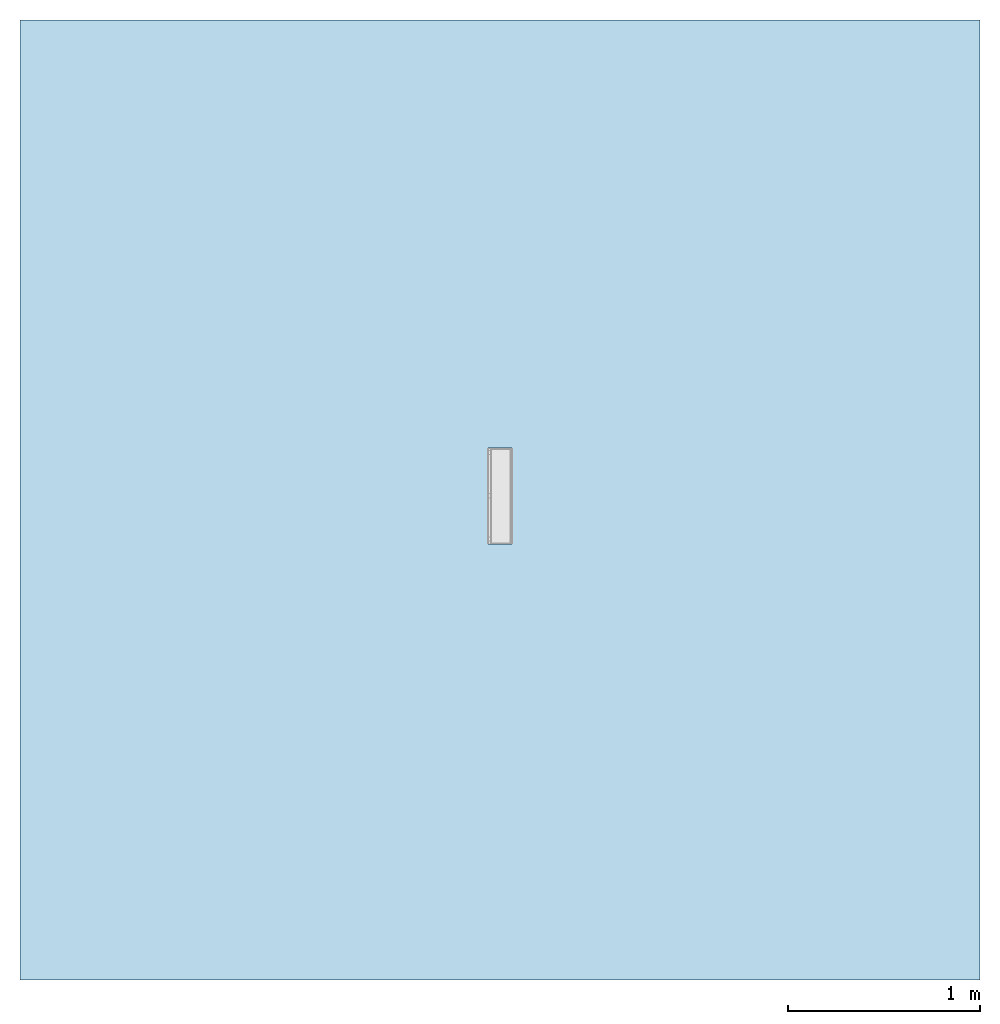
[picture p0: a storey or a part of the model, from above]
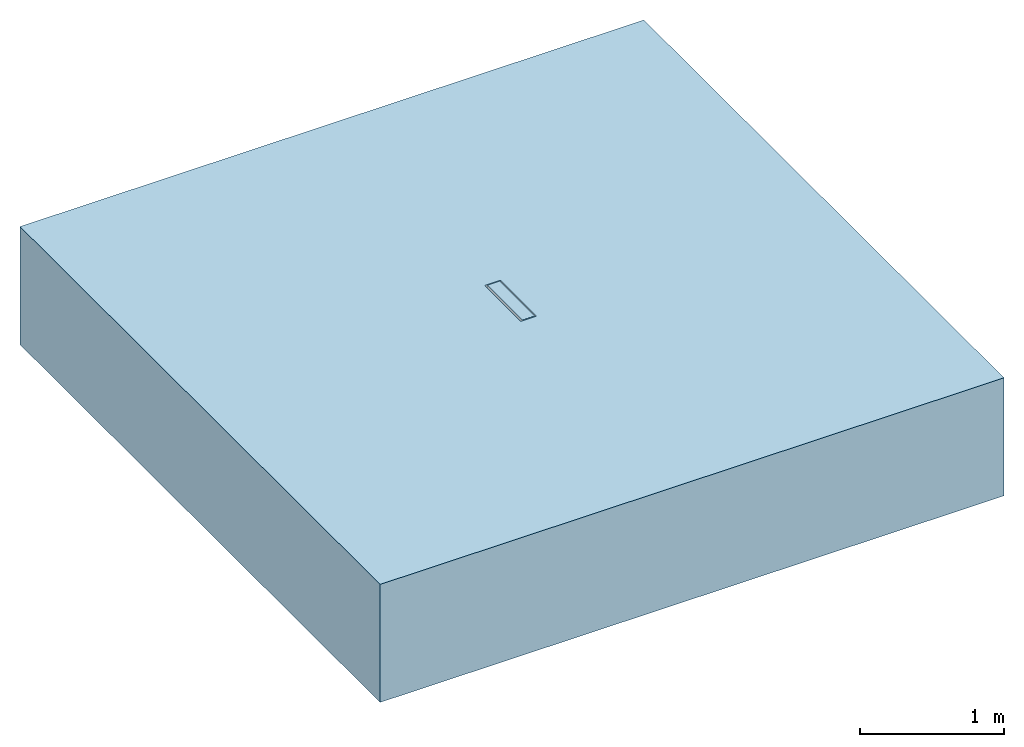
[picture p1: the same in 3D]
Properties of the parts of a building model (IFC2X3)

# File
Description: ViewDefinition [CoordinationView]
File name: 24410.ifc
Time: 2013-10-30T12:05:11
Written by: Autodesk Revit 2013
Made in: 20120221_2030(x64)

# IfcProject, Project Number
LongName: Project Name; Phase: Project Status

# IfcSite, Default
RefLatitude: 42, 21, 30, 344238; RefLongitude: -71, -3, -35, -194702; RefElevation: 0 mm

# IfcBuilding
Pset_BuildingCommon - NumberOfStoreys: 1
Other - Project Issue Date: Issue Date; Client Name: Owner; Project Status: Project Status; Project Address: ## Street City, State Zip; Project Name: Project Name; Project Number: Project Number

# IfcBuildingStorey, Level 1
LongName: Level 1; Elevation: 0 mm
Constraints - Elevation Base: 0; Elevation: 0 mm
Graphics - Line Weight: 1; Line Pattern: Center; Symbol at End 1 Default: no; Color: 0; Symbol: M_Level Head - Circle: M_Level Head - Circle; Symbol at End 2 Default: yes
Identity Data - Building Story: yes; Name: Level 1; Structural: no
Dimensions - Computation Height: 0 mm

# IfcBuildingElementProxy: 24410 - Universal Sump Unit - 500mm LG, Civil-Drainage-Channel-ACO-MultiDrain-M100DS-Brickslot-Channel-System:24410 - Universal Sump Unit - 500mm LG:24410 - Universal Sump Unit - 500mm LG:196059
In: Level 1
Material: Vienite® Synthetic Resin Concrete, Phenolic Resin, Plastic, Opaque Black, Stainless Steel (F)
Materials and Finishes - Channel Colour: Brown; Channel Material: Vienite® Synthetic Resin Concrete; Edge Rail Colour: Self; Edge Rail Material: Stainless Steel Grade 304
Dimensions - EndCap Position: 500 mm; Custom_Void_length: 500 mm; Brickslot Void Length: 500 mm; Brickslot Void Depth: 6000 mm; FloorCut_Length: -500 mm; Volume: 16336718 mm3; Brickslot Access Unit Void Depth: 0 mm; Brickslot Access Unit Void Bottom Depth: -105 mm; Length: 1000 mm; ShallowInvDepth: 55 mm; FloorCut_Width: 135 mm; ShallowOverallDepth: 75 mm; Brickslot Access Unit Floor Cut Length: 500 mm; Depth: 150 mm; GratingLength: -1000 mm; Length Drain: -500 mm; FloorCut_Depth: 635 mm; EndCap_Height: 249 mm; Floor Cut Gap: 105 mm; InvDepth: 80 mm
Construction - 23404_Universal Endcap (Male End): no; 23477_Load Class C250 & D400_Brickslot_Access Unit_Stainless Steel_500mm Long: yes; 23476_Load Class C250 & D400_Brickslot Grating_Stainless Steel_500mm Long: no; 23404_Universal Endcap (Female End): no; 23475_Load Class C250 & D400_Brickslot Grating_Stainless Steel_1000mm Long: no; 23410_Sump Unit: yes; Shallow Depth Channel with seal: no; Shallow Depth Channel: no; Constant Depth Junction Channel: no; Constant Depth Channel: no
Constraints - Level: Level: Level 1; Moves With Nearby Elements: no
Phasing - Phase Created: New Construction
Pset_BuildingElementProxyCommon - Reference: 24410 - Universal Sump Unit - 500mm LG
Model Properties - Brickslot Grating Product code 23476: Load Class C250/D400 - Brickslot Stainless Steel - 500mm long x 105mm high - Intake area -10mm Slot- 1000mm²/m - 3.3 Kg; Brickslot Grating Product code 23475: N/A; End Cap Product code 23404: No 306 Universl End Cap - 135mm wide x 300mm long - Spigot Ø110mm x 50mm long - Silver - Polypropylene - 0.16kg; Brickslot Access Unit Product code 23477: Load Class C250/D400 - Brickslot Access Unit Stainless Steel - 500mm long x 105mm high -10mm Slot- Intake area - 1000mm²/m - 6.4 Kg
Data - Pre-formed Outlet Ø: 110mm / 160mm; Concrete Surround Volume - Load Class B 125 - C 250 - Concrete Pavement: N/A; ACO Hydraulic Design Software: http://www.acodesign.co.uk; Installation - Concrete Grade: Refer to brochure; Concrete Surround Volume - Load Class D 400 - Concrete Pavement: N/A; Product Weight: 33.9 Kg; Concrete Surround Volume - Load Class A 15 - Concrete Pavement: N/A; Hydraulic Performance: http://www.aco.co.uk/download.php?id=173; Product Dimensions: 500mm x 135mm x 635mm (LxWxH); Product Standard: BS EN 1433:2002, CE marked; Channel C.S.A: N/A; Invert Depth: 615mm; Load Class: A 15 - D 400
Identity Data - Watermarked With: BIM Manager Premium Suite; Product Code: 24410; Type Comments: ACO MultiDrain M100DS Sump Unit 500mm Long; Product Page URL: http://www.aco.co.uk/product_detail.php?id=58; Maintenance guidelines: http://www.aco.co.uk/download.php?id=173; OmniClass Title: Rainwater Removal; Assembly Description: Rain Water Drainage; URL: www.aco.co.uk; Product brochure: http://www.aco.co.uk/download.php?id=173; Model: ACO MultiDrain MDS Brickslot- M100DS; Address: ACO Business Park, Hitchin Road, Shefford, Bedfordshire, United Kingdom SG17 5TE; OmniClass Number: 23.70.50.24; e-mail Sales: customersupport@aco.co.uk; Watermarked By: www.aco.co.uk; Price: POA - contact ACO; e-mail Technical: technical@aco.co.uk; Assembly Code: D2040; Cost: 0; Manufacturer: ACO Technologies plc - ACO Water Management Division; Telephone: +44 (0)1462 816666; Installation guidelines: http://www.aco.co.uk/download.php?id=173; Fax: +44 (0)1462 815895; Watermark 2: This file is water marked and users are prohibited to reproduce, adapt, distribute this information; Watermark 1: This file is the property of ACO Technologies PLC; Model Description: Channel drainage system
Other - Revision: 1; Created By: www.aco.co.uk
General - TagNumber: 0; SerialNumber: 0
Green Building Properties - Channel Recyclable: Fully recyclable; Edge Rail Recyclable: Fully recyclable; Edge Rail Recycled Material Content: Between 40% - 90%; Channel Recycled Material Content: 20% minimum

# IfcOpeningElement: Recess (2)
In: Level 1
Constraints - Height Offset From Level: 0 mm; Room Bounding: yes; Level: Level: Level 1; Related to Mass: no
Dimensions - Volume: 24955543390 mm3; Area: 25000000 mm2; Thickness: 1000 mm; Perimeter: 20000 mm
Structural - Enable Analytical Model: no; Structural: no
Phasing - Phase Created: New Construction
Construction - Default Thickness: 1000 mm; Function: 0
Analytical Properties - Heat Transfer Coefficient (U): 0.837; Thermal mass: 1359800; Roughness: 1; Absorptance: 0.1; Thermal Resistance (R): 1.19474
Materials and Finishes - Structural Material: Earth
Graphics - Coarse Scale Fill Color: 0

# IfcSlab: Floor:Generic Floor - 1000mm, Floor:Generic Floor - 1000mm:193825
In: Level 1
PredefinedType: FLOOR; Material: Earth 1000 mm
Constraints - Height Offset From Level: 0 mm; Room Bounding: yes; Level: Level: Level 1; Related to Mass: no
Dimensions - Volume: 24955543390 mm3; Area: 25000000 mm2; Thickness: 1000 mm; Perimeter: 20000 mm
Structural - Enable Analytical Model: no; Structural: no
Phasing - Phase Created: New Construction
Pset_SlabCommon - Reference: Generic Floor - 1000mm; IsExternal: no; LoadBearing: yes
Construction - Default Thickness: 1000 mm; Function: 0
Analytical Properties - Heat Transfer Coefficient (U): 0.837; Thermal mass: 1359800; Roughness: 1; Absorptance: 0.1; Thermal Resistance (R): 1.19474
Materials and Finishes - Structural Material: Earth
Graphics - Coarse Scale Fill Color: 0
